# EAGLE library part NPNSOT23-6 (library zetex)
NPN TRANSISTOR

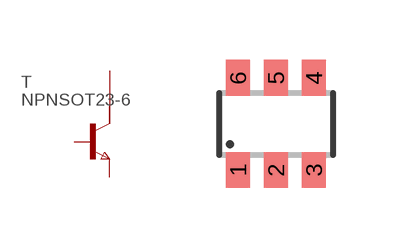
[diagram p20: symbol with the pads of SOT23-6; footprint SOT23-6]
Designator prefix T

## NPNSOT23-6  [SOT23-6]
1  C1  pas
2  C2  pas
3  B  pas
4  E  pas
5  C3  pas
6  C4  pas

## Footprint SOT23-6 (pad centres in mm)
Small Outline Transistor 6 lead
smd 0.6 x 0.9: 1 -0.95,-1.15; 2 0,-1.15; 3 0.95,-1.15; 4 0.95,1.15; 5 0,1.15; 6 -0.95,1.15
